VERSION 5.8 ;
BUSBITCHARS "[]" ;
DIVIDERCHAR "/" ;
UNITS
    DATABASE MICRONS 2000 ;
END UNITS

VIA uart_rx_via1_2_8960_1800_2_8_1040_1040
  VIARULE Via1_GEN_HH ;
  CUTSIZE 0.26 0.26 ;
  LAYERS Metal1 Via1 Metal2 ;
  CUTSPACING 0.26 0.26 ;
  ENCLOSURE 0.06 0.06 0.01 0.06 ;
  ROWCOL 2 8 ;
END uart_rx_via1_2_8960_1800_2_8_1040_1040

VIA uart_rx_via2_3_8960_1800_2_8_1040_1040
  VIARULE Via2_GEN_HH ;
  CUTSIZE 0.26 0.26 ;
  LAYERS Metal2 Via2 Metal3 ;
  CUTSPACING 0.26 0.26 ;
  ENCLOSURE 0.01 0.06 0.06 0.01 ;
  ROWCOL 2 8 ;
END uart_rx_via2_3_8960_1800_2_8_1040_1040

VIA uart_rx_via3_4_8960_1800_2_8_1040_1040
  VIARULE Via3_GEN_HH ;
  CUTSIZE 0.26 0.26 ;
  LAYERS Metal3 Via3 Metal4 ;
  CUTSPACING 0.26 0.26 ;
  ENCLOSURE 0.06 0.01 0.29 0.06 ;
  ROWCOL 2 8 ;
END uart_rx_via3_4_8960_1800_2_8_1040_1040

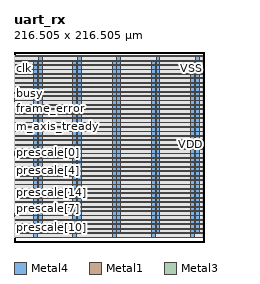
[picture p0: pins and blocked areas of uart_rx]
MACRO uart_rx
  FOREIGN uart_rx 0 0 ;
  CLASS BLOCK ;
  SIZE 216.505 BY 216.505 ;
  PIN VDD
    USE POWER ;
    DIRECTION INOUT ;
    PORT
      LAYER Metal4 ;
        RECT  206.64 9.63 211.12 212.13 ;
        RECT  161.84 9.63 166.32 212.13 ;
        RECT  117.04 9.63 121.52 212.13 ;
        RECT  72.24 9.63 76.72 212.13 ;
        RECT  27.44 9.63 31.92 212.13 ;
      LAYER Metal1 ;
        RECT  2.24 211.23 214.48 212.13 ;
        RECT  2.24 201.15 214.48 202.05 ;
        RECT  2.24 191.07 214.48 191.97 ;
        RECT  2.24 180.99 214.48 181.89 ;
        RECT  2.24 170.91 214.48 171.81 ;
        RECT  2.24 160.83 214.48 161.73 ;
        RECT  2.24 150.75 214.48 151.65 ;
        RECT  2.24 140.67 214.48 141.57 ;
        RECT  2.24 130.59 214.48 131.49 ;
        RECT  2.24 120.51 214.48 121.41 ;
        RECT  2.24 110.43 214.48 111.33 ;
        RECT  2.24 100.35 214.48 101.25 ;
        RECT  2.24 90.27 214.48 91.17 ;
        RECT  2.24 80.19 214.48 81.09 ;
        RECT  2.24 70.11 214.48 71.01 ;
        RECT  2.24 60.03 214.48 60.93 ;
        RECT  2.24 49.95 214.48 50.85 ;
        RECT  2.24 39.87 214.48 40.77 ;
        RECT  2.24 29.79 214.48 30.69 ;
        RECT  2.24 19.71 214.48 20.61 ;
        RECT  2.24 9.63 214.48 10.53 ;
      VIA 208.88 211.68 uart_rx_via3_4_8960_1800_2_8_1040_1040 ;
      VIA 208.88 211.68 uart_rx_via2_3_8960_1800_2_8_1040_1040 ;
      VIA 208.88 211.68 uart_rx_via1_2_8960_1800_2_8_1040_1040 ;
      VIA 208.88 201.6 uart_rx_via3_4_8960_1800_2_8_1040_1040 ;
      VIA 208.88 201.6 uart_rx_via2_3_8960_1800_2_8_1040_1040 ;
      VIA 208.88 201.6 uart_rx_via1_2_8960_1800_2_8_1040_1040 ;
      VIA 208.88 191.52 uart_rx_via3_4_8960_1800_2_8_1040_1040 ;
      VIA 208.88 191.52 uart_rx_via2_3_8960_1800_2_8_1040_1040 ;
      VIA 208.88 191.52 uart_rx_via1_2_8960_1800_2_8_1040_1040 ;
      VIA 208.88 181.44 uart_rx_via3_4_8960_1800_2_8_1040_1040 ;
      VIA 208.88 181.44 uart_rx_via2_3_8960_1800_2_8_1040_1040 ;
      VIA 208.88 181.44 uart_rx_via1_2_8960_1800_2_8_1040_1040 ;
      VIA 208.88 171.36 uart_rx_via3_4_8960_1800_2_8_1040_1040 ;
      VIA 208.88 171.36 uart_rx_via2_3_8960_1800_2_8_1040_1040 ;
      VIA 208.88 171.36 uart_rx_via1_2_8960_1800_2_8_1040_1040 ;
      VIA 208.88 161.28 uart_rx_via3_4_8960_1800_2_8_1040_1040 ;
      VIA 208.88 161.28 uart_rx_via2_3_8960_1800_2_8_1040_1040 ;
      VIA 208.88 161.28 uart_rx_via1_2_8960_1800_2_8_1040_1040 ;
      VIA 208.88 151.2 uart_rx_via3_4_8960_1800_2_8_1040_1040 ;
      VIA 208.88 151.2 uart_rx_via2_3_8960_1800_2_8_1040_1040 ;
      VIA 208.88 151.2 uart_rx_via1_2_8960_1800_2_8_1040_1040 ;
      VIA 208.88 141.12 uart_rx_via3_4_8960_1800_2_8_1040_1040 ;
      VIA 208.88 141.12 uart_rx_via2_3_8960_1800_2_8_1040_1040 ;
      VIA 208.88 141.12 uart_rx_via1_2_8960_1800_2_8_1040_1040 ;
      VIA 208.88 131.04 uart_rx_via3_4_8960_1800_2_8_1040_1040 ;
      VIA 208.88 131.04 uart_rx_via2_3_8960_1800_2_8_1040_1040 ;
      VIA 208.88 131.04 uart_rx_via1_2_8960_1800_2_8_1040_1040 ;
      VIA 208.88 120.96 uart_rx_via3_4_8960_1800_2_8_1040_1040 ;
      VIA 208.88 120.96 uart_rx_via2_3_8960_1800_2_8_1040_1040 ;
      VIA 208.88 120.96 uart_rx_via1_2_8960_1800_2_8_1040_1040 ;
      VIA 208.88 110.88 uart_rx_via3_4_8960_1800_2_8_1040_1040 ;
      VIA 208.88 110.88 uart_rx_via2_3_8960_1800_2_8_1040_1040 ;
      VIA 208.88 110.88 uart_rx_via1_2_8960_1800_2_8_1040_1040 ;
      VIA 208.88 100.8 uart_rx_via3_4_8960_1800_2_8_1040_1040 ;
      VIA 208.88 100.8 uart_rx_via2_3_8960_1800_2_8_1040_1040 ;
      VIA 208.88 100.8 uart_rx_via1_2_8960_1800_2_8_1040_1040 ;
      VIA 208.88 90.72 uart_rx_via3_4_8960_1800_2_8_1040_1040 ;
      VIA 208.88 90.72 uart_rx_via2_3_8960_1800_2_8_1040_1040 ;
      VIA 208.88 90.72 uart_rx_via1_2_8960_1800_2_8_1040_1040 ;
      VIA 208.88 80.64 uart_rx_via3_4_8960_1800_2_8_1040_1040 ;
      VIA 208.88 80.64 uart_rx_via2_3_8960_1800_2_8_1040_1040 ;
      VIA 208.88 80.64 uart_rx_via1_2_8960_1800_2_8_1040_1040 ;
      VIA 208.88 70.56 uart_rx_via3_4_8960_1800_2_8_1040_1040 ;
      VIA 208.88 70.56 uart_rx_via2_3_8960_1800_2_8_1040_1040 ;
      VIA 208.88 70.56 uart_rx_via1_2_8960_1800_2_8_1040_1040 ;
      VIA 208.88 60.48 uart_rx_via3_4_8960_1800_2_8_1040_1040 ;
      VIA 208.88 60.48 uart_rx_via2_3_8960_1800_2_8_1040_1040 ;
      VIA 208.88 60.48 uart_rx_via1_2_8960_1800_2_8_1040_1040 ;
      VIA 208.88 50.4 uart_rx_via3_4_8960_1800_2_8_1040_1040 ;
      VIA 208.88 50.4 uart_rx_via2_3_8960_1800_2_8_1040_1040 ;
      VIA 208.88 50.4 uart_rx_via1_2_8960_1800_2_8_1040_1040 ;
      VIA 208.88 40.32 uart_rx_via3_4_8960_1800_2_8_1040_1040 ;
      VIA 208.88 40.32 uart_rx_via2_3_8960_1800_2_8_1040_1040 ;
      VIA 208.88 40.32 uart_rx_via1_2_8960_1800_2_8_1040_1040 ;
      VIA 208.88 30.24 uart_rx_via3_4_8960_1800_2_8_1040_1040 ;
      VIA 208.88 30.24 uart_rx_via2_3_8960_1800_2_8_1040_1040 ;
      VIA 208.88 30.24 uart_rx_via1_2_8960_1800_2_8_1040_1040 ;
      VIA 208.88 20.16 uart_rx_via3_4_8960_1800_2_8_1040_1040 ;
      VIA 208.88 20.16 uart_rx_via2_3_8960_1800_2_8_1040_1040 ;
      VIA 208.88 20.16 uart_rx_via1_2_8960_1800_2_8_1040_1040 ;
      VIA 208.88 10.08 uart_rx_via3_4_8960_1800_2_8_1040_1040 ;
      VIA 208.88 10.08 uart_rx_via2_3_8960_1800_2_8_1040_1040 ;
      VIA 208.88 10.08 uart_rx_via1_2_8960_1800_2_8_1040_1040 ;
      VIA 164.08 211.68 uart_rx_via3_4_8960_1800_2_8_1040_1040 ;
      VIA 164.08 211.68 uart_rx_via2_3_8960_1800_2_8_1040_1040 ;
      VIA 164.08 211.68 uart_rx_via1_2_8960_1800_2_8_1040_1040 ;
      VIA 164.08 201.6 uart_rx_via3_4_8960_1800_2_8_1040_1040 ;
      VIA 164.08 201.6 uart_rx_via2_3_8960_1800_2_8_1040_1040 ;
      VIA 164.08 201.6 uart_rx_via1_2_8960_1800_2_8_1040_1040 ;
      VIA 164.08 191.52 uart_rx_via3_4_8960_1800_2_8_1040_1040 ;
      VIA 164.08 191.52 uart_rx_via2_3_8960_1800_2_8_1040_1040 ;
      VIA 164.08 191.52 uart_rx_via1_2_8960_1800_2_8_1040_1040 ;
      VIA 164.08 181.44 uart_rx_via3_4_8960_1800_2_8_1040_1040 ;
      VIA 164.08 181.44 uart_rx_via2_3_8960_1800_2_8_1040_1040 ;
      VIA 164.08 181.44 uart_rx_via1_2_8960_1800_2_8_1040_1040 ;
      VIA 164.08 171.36 uart_rx_via3_4_8960_1800_2_8_1040_1040 ;
      VIA 164.08 171.36 uart_rx_via2_3_8960_1800_2_8_1040_1040 ;
      VIA 164.08 171.36 uart_rx_via1_2_8960_1800_2_8_1040_1040 ;
      VIA 164.08 161.28 uart_rx_via3_4_8960_1800_2_8_1040_1040 ;
      VIA 164.08 161.28 uart_rx_via2_3_8960_1800_2_8_1040_1040 ;
      VIA 164.08 161.28 uart_rx_via1_2_8960_1800_2_8_1040_1040 ;
      VIA 164.08 151.2 uart_rx_via3_4_8960_1800_2_8_1040_1040 ;
      VIA 164.08 151.2 uart_rx_via2_3_8960_1800_2_8_1040_1040 ;
      VIA 164.08 151.2 uart_rx_via1_2_8960_1800_2_8_1040_1040 ;
      VIA 164.08 141.12 uart_rx_via3_4_8960_1800_2_8_1040_1040 ;
      VIA 164.08 141.12 uart_rx_via2_3_8960_1800_2_8_1040_1040 ;
      VIA 164.08 141.12 uart_rx_via1_2_8960_1800_2_8_1040_1040 ;
      VIA 164.08 131.04 uart_rx_via3_4_8960_1800_2_8_1040_1040 ;
      VIA 164.08 131.04 uart_rx_via2_3_8960_1800_2_8_1040_1040 ;
      VIA 164.08 131.04 uart_rx_via1_2_8960_1800_2_8_1040_1040 ;
      VIA 164.08 120.96 uart_rx_via3_4_8960_1800_2_8_1040_1040 ;
      VIA 164.08 120.96 uart_rx_via2_3_8960_1800_2_8_1040_1040 ;
      VIA 164.08 120.96 uart_rx_via1_2_8960_1800_2_8_1040_1040 ;
      VIA 164.08 110.88 uart_rx_via3_4_8960_1800_2_8_1040_1040 ;
      VIA 164.08 110.88 uart_rx_via2_3_8960_1800_2_8_1040_1040 ;
      VIA 164.08 110.88 uart_rx_via1_2_8960_1800_2_8_1040_1040 ;
      VIA 164.08 100.8 uart_rx_via3_4_8960_1800_2_8_1040_1040 ;
      VIA 164.08 100.8 uart_rx_via2_3_8960_1800_2_8_1040_1040 ;
      VIA 164.08 100.8 uart_rx_via1_2_8960_1800_2_8_1040_1040 ;
      VIA 164.08 90.72 uart_rx_via3_4_8960_1800_2_8_1040_1040 ;
      VIA 164.08 90.72 uart_rx_via2_3_8960_1800_2_8_1040_1040 ;
      VIA 164.08 90.72 uart_rx_via1_2_8960_1800_2_8_1040_1040 ;
      VIA 164.08 80.64 uart_rx_via3_4_8960_1800_2_8_1040_1040 ;
      VIA 164.08 80.64 uart_rx_via2_3_8960_1800_2_8_1040_1040 ;
      VIA 164.08 80.64 uart_rx_via1_2_8960_1800_2_8_1040_1040 ;
      VIA 164.08 70.56 uart_rx_via3_4_8960_1800_2_8_1040_1040 ;
      VIA 164.08 70.56 uart_rx_via2_3_8960_1800_2_8_1040_1040 ;
      VIA 164.08 70.56 uart_rx_via1_2_8960_1800_2_8_1040_1040 ;
      VIA 164.08 60.48 uart_rx_via3_4_8960_1800_2_8_1040_1040 ;
      VIA 164.08 60.48 uart_rx_via2_3_8960_1800_2_8_1040_1040 ;
      VIA 164.08 60.48 uart_rx_via1_2_8960_1800_2_8_1040_1040 ;
      VIA 164.08 50.4 uart_rx_via3_4_8960_1800_2_8_1040_1040 ;
      VIA 164.08 50.4 uart_rx_via2_3_8960_1800_2_8_1040_1040 ;
      VIA 164.08 50.4 uart_rx_via1_2_8960_1800_2_8_1040_1040 ;
      VIA 164.08 40.32 uart_rx_via3_4_8960_1800_2_8_1040_1040 ;
      VIA 164.08 40.32 uart_rx_via2_3_8960_1800_2_8_1040_1040 ;
      VIA 164.08 40.32 uart_rx_via1_2_8960_1800_2_8_1040_1040 ;
      VIA 164.08 30.24 uart_rx_via3_4_8960_1800_2_8_1040_1040 ;
      VIA 164.08 30.24 uart_rx_via2_3_8960_1800_2_8_1040_1040 ;
      VIA 164.08 30.24 uart_rx_via1_2_8960_1800_2_8_1040_1040 ;
      VIA 164.08 20.16 uart_rx_via3_4_8960_1800_2_8_1040_1040 ;
      VIA 164.08 20.16 uart_rx_via2_3_8960_1800_2_8_1040_1040 ;
      VIA 164.08 20.16 uart_rx_via1_2_8960_1800_2_8_1040_1040 ;
      VIA 164.08 10.08 uart_rx_via3_4_8960_1800_2_8_1040_1040 ;
      VIA 164.08 10.08 uart_rx_via2_3_8960_1800_2_8_1040_1040 ;
      VIA 164.08 10.08 uart_rx_via1_2_8960_1800_2_8_1040_1040 ;
      VIA 119.28 211.68 uart_rx_via3_4_8960_1800_2_8_1040_1040 ;
      VIA 119.28 211.68 uart_rx_via2_3_8960_1800_2_8_1040_1040 ;
      VIA 119.28 211.68 uart_rx_via1_2_8960_1800_2_8_1040_1040 ;
      VIA 119.28 201.6 uart_rx_via3_4_8960_1800_2_8_1040_1040 ;
      VIA 119.28 201.6 uart_rx_via2_3_8960_1800_2_8_1040_1040 ;
      VIA 119.28 201.6 uart_rx_via1_2_8960_1800_2_8_1040_1040 ;
      VIA 119.28 191.52 uart_rx_via3_4_8960_1800_2_8_1040_1040 ;
      VIA 119.28 191.52 uart_rx_via2_3_8960_1800_2_8_1040_1040 ;
      VIA 119.28 191.52 uart_rx_via1_2_8960_1800_2_8_1040_1040 ;
      VIA 119.28 181.44 uart_rx_via3_4_8960_1800_2_8_1040_1040 ;
      VIA 119.28 181.44 uart_rx_via2_3_8960_1800_2_8_1040_1040 ;
      VIA 119.28 181.44 uart_rx_via1_2_8960_1800_2_8_1040_1040 ;
      VIA 119.28 171.36 uart_rx_via3_4_8960_1800_2_8_1040_1040 ;
      VIA 119.28 171.36 uart_rx_via2_3_8960_1800_2_8_1040_1040 ;
      VIA 119.28 171.36 uart_rx_via1_2_8960_1800_2_8_1040_1040 ;
      VIA 119.28 161.28 uart_rx_via3_4_8960_1800_2_8_1040_1040 ;
      VIA 119.28 161.28 uart_rx_via2_3_8960_1800_2_8_1040_1040 ;
      VIA 119.28 161.28 uart_rx_via1_2_8960_1800_2_8_1040_1040 ;
      VIA 119.28 151.2 uart_rx_via3_4_8960_1800_2_8_1040_1040 ;
      VIA 119.28 151.2 uart_rx_via2_3_8960_1800_2_8_1040_1040 ;
      VIA 119.28 151.2 uart_rx_via1_2_8960_1800_2_8_1040_1040 ;
      VIA 119.28 141.12 uart_rx_via3_4_8960_1800_2_8_1040_1040 ;
      VIA 119.28 141.12 uart_rx_via2_3_8960_1800_2_8_1040_1040 ;
      VIA 119.28 141.12 uart_rx_via1_2_8960_1800_2_8_1040_1040 ;
      VIA 119.28 131.04 uart_rx_via3_4_8960_1800_2_8_1040_1040 ;
      VIA 119.28 131.04 uart_rx_via2_3_8960_1800_2_8_1040_1040 ;
      VIA 119.28 131.04 uart_rx_via1_2_8960_1800_2_8_1040_1040 ;
      VIA 119.28 120.96 uart_rx_via3_4_8960_1800_2_8_1040_1040 ;
      VIA 119.28 120.96 uart_rx_via2_3_8960_1800_2_8_1040_1040 ;
      VIA 119.28 120.96 uart_rx_via1_2_8960_1800_2_8_1040_1040 ;
      VIA 119.28 110.88 uart_rx_via3_4_8960_1800_2_8_1040_1040 ;
      VIA 119.28 110.88 uart_rx_via2_3_8960_1800_2_8_1040_1040 ;
      VIA 119.28 110.88 uart_rx_via1_2_8960_1800_2_8_1040_1040 ;
      VIA 119.28 100.8 uart_rx_via3_4_8960_1800_2_8_1040_1040 ;
      VIA 119.28 100.8 uart_rx_via2_3_8960_1800_2_8_1040_1040 ;
      VIA 119.28 100.8 uart_rx_via1_2_8960_1800_2_8_1040_1040 ;
      VIA 119.28 90.72 uart_rx_via3_4_8960_1800_2_8_1040_1040 ;
      VIA 119.28 90.72 uart_rx_via2_3_8960_1800_2_8_1040_1040 ;
      VIA 119.28 90.72 uart_rx_via1_2_8960_1800_2_8_1040_1040 ;
      VIA 119.28 80.64 uart_rx_via3_4_8960_1800_2_8_1040_1040 ;
      VIA 119.28 80.64 uart_rx_via2_3_8960_1800_2_8_1040_1040 ;
      VIA 119.28 80.64 uart_rx_via1_2_8960_1800_2_8_1040_1040 ;
      VIA 119.28 70.56 uart_rx_via3_4_8960_1800_2_8_1040_1040 ;
      VIA 119.28 70.56 uart_rx_via2_3_8960_1800_2_8_1040_1040 ;
      VIA 119.28 70.56 uart_rx_via1_2_8960_1800_2_8_1040_1040 ;
      VIA 119.28 60.48 uart_rx_via3_4_8960_1800_2_8_1040_1040 ;
      VIA 119.28 60.48 uart_rx_via2_3_8960_1800_2_8_1040_1040 ;
      VIA 119.28 60.48 uart_rx_via1_2_8960_1800_2_8_1040_1040 ;
      VIA 119.28 50.4 uart_rx_via3_4_8960_1800_2_8_1040_1040 ;
      VIA 119.28 50.4 uart_rx_via2_3_8960_1800_2_8_1040_1040 ;
      VIA 119.28 50.4 uart_rx_via1_2_8960_1800_2_8_1040_1040 ;
      VIA 119.28 40.32 uart_rx_via3_4_8960_1800_2_8_1040_1040 ;
      VIA 119.28 40.32 uart_rx_via2_3_8960_1800_2_8_1040_1040 ;
      VIA 119.28 40.32 uart_rx_via1_2_8960_1800_2_8_1040_1040 ;
      VIA 119.28 30.24 uart_rx_via3_4_8960_1800_2_8_1040_1040 ;
      VIA 119.28 30.24 uart_rx_via2_3_8960_1800_2_8_1040_1040 ;
      VIA 119.28 30.24 uart_rx_via1_2_8960_1800_2_8_1040_1040 ;
      VIA 119.28 20.16 uart_rx_via3_4_8960_1800_2_8_1040_1040 ;
      VIA 119.28 20.16 uart_rx_via2_3_8960_1800_2_8_1040_1040 ;
      VIA 119.28 20.16 uart_rx_via1_2_8960_1800_2_8_1040_1040 ;
      VIA 119.28 10.08 uart_rx_via3_4_8960_1800_2_8_1040_1040 ;
      VIA 119.28 10.08 uart_rx_via2_3_8960_1800_2_8_1040_1040 ;
      VIA 119.28 10.08 uart_rx_via1_2_8960_1800_2_8_1040_1040 ;
      VIA 74.48 211.68 uart_rx_via3_4_8960_1800_2_8_1040_1040 ;
      VIA 74.48 211.68 uart_rx_via2_3_8960_1800_2_8_1040_1040 ;
      VIA 74.48 211.68 uart_rx_via1_2_8960_1800_2_8_1040_1040 ;
      VIA 74.48 201.6 uart_rx_via3_4_8960_1800_2_8_1040_1040 ;
      VIA 74.48 201.6 uart_rx_via2_3_8960_1800_2_8_1040_1040 ;
      VIA 74.48 201.6 uart_rx_via1_2_8960_1800_2_8_1040_1040 ;
      VIA 74.48 191.52 uart_rx_via3_4_8960_1800_2_8_1040_1040 ;
      VIA 74.48 191.52 uart_rx_via2_3_8960_1800_2_8_1040_1040 ;
      VIA 74.48 191.52 uart_rx_via1_2_8960_1800_2_8_1040_1040 ;
      VIA 74.48 181.44 uart_rx_via3_4_8960_1800_2_8_1040_1040 ;
      VIA 74.48 181.44 uart_rx_via2_3_8960_1800_2_8_1040_1040 ;
      VIA 74.48 181.44 uart_rx_via1_2_8960_1800_2_8_1040_1040 ;
      VIA 74.48 171.36 uart_rx_via3_4_8960_1800_2_8_1040_1040 ;
      VIA 74.48 171.36 uart_rx_via2_3_8960_1800_2_8_1040_1040 ;
      VIA 74.48 171.36 uart_rx_via1_2_8960_1800_2_8_1040_1040 ;
      VIA 74.48 161.28 uart_rx_via3_4_8960_1800_2_8_1040_1040 ;
      VIA 74.48 161.28 uart_rx_via2_3_8960_1800_2_8_1040_1040 ;
      VIA 74.48 161.28 uart_rx_via1_2_8960_1800_2_8_1040_1040 ;
      VIA 74.48 151.2 uart_rx_via3_4_8960_1800_2_8_1040_1040 ;
      VIA 74.48 151.2 uart_rx_via2_3_8960_1800_2_8_1040_1040 ;
      VIA 74.48 151.2 uart_rx_via1_2_8960_1800_2_8_1040_1040 ;
      VIA 74.48 141.12 uart_rx_via3_4_8960_1800_2_8_1040_1040 ;
      VIA 74.48 141.12 uart_rx_via2_3_8960_1800_2_8_1040_1040 ;
      VIA 74.48 141.12 uart_rx_via1_2_8960_1800_2_8_1040_1040 ;
      VIA 74.48 131.04 uart_rx_via3_4_8960_1800_2_8_1040_1040 ;
      VIA 74.48 131.04 uart_rx_via2_3_8960_1800_2_8_1040_1040 ;
      VIA 74.48 131.04 uart_rx_via1_2_8960_1800_2_8_1040_1040 ;
      VIA 74.48 120.96 uart_rx_via3_4_8960_1800_2_8_1040_1040 ;
      VIA 74.48 120.96 uart_rx_via2_3_8960_1800_2_8_1040_1040 ;
      VIA 74.48 120.96 uart_rx_via1_2_8960_1800_2_8_1040_1040 ;
      VIA 74.48 110.88 uart_rx_via3_4_8960_1800_2_8_1040_1040 ;
      VIA 74.48 110.88 uart_rx_via2_3_8960_1800_2_8_1040_1040 ;
      VIA 74.48 110.88 uart_rx_via1_2_8960_1800_2_8_1040_1040 ;
      VIA 74.48 100.8 uart_rx_via3_4_8960_1800_2_8_1040_1040 ;
      VIA 74.48 100.8 uart_rx_via2_3_8960_1800_2_8_1040_1040 ;
      VIA 74.48 100.8 uart_rx_via1_2_8960_1800_2_8_1040_1040 ;
      VIA 74.48 90.72 uart_rx_via3_4_8960_1800_2_8_1040_1040 ;
      VIA 74.48 90.72 uart_rx_via2_3_8960_1800_2_8_1040_1040 ;
      VIA 74.48 90.72 uart_rx_via1_2_8960_1800_2_8_1040_1040 ;
      VIA 74.48 80.64 uart_rx_via3_4_8960_1800_2_8_1040_1040 ;
      VIA 74.48 80.64 uart_rx_via2_3_8960_1800_2_8_1040_1040 ;
      VIA 74.48 80.64 uart_rx_via1_2_8960_1800_2_8_1040_1040 ;
      VIA 74.48 70.56 uart_rx_via3_4_8960_1800_2_8_1040_1040 ;
      VIA 74.48 70.56 uart_rx_via2_3_8960_1800_2_8_1040_1040 ;
      VIA 74.48 70.56 uart_rx_via1_2_8960_1800_2_8_1040_1040 ;
      VIA 74.48 60.48 uart_rx_via3_4_8960_1800_2_8_1040_1040 ;
      VIA 74.48 60.48 uart_rx_via2_3_8960_1800_2_8_1040_1040 ;
      VIA 74.48 60.48 uart_rx_via1_2_8960_1800_2_8_1040_1040 ;
      VIA 74.48 50.4 uart_rx_via3_4_8960_1800_2_8_1040_1040 ;
      VIA 74.48 50.4 uart_rx_via2_3_8960_1800_2_8_1040_1040 ;
      VIA 74.48 50.4 uart_rx_via1_2_8960_1800_2_8_1040_1040 ;
      VIA 74.48 40.32 uart_rx_via3_4_8960_1800_2_8_1040_1040 ;
      VIA 74.48 40.32 uart_rx_via2_3_8960_1800_2_8_1040_1040 ;
      VIA 74.48 40.32 uart_rx_via1_2_8960_1800_2_8_1040_1040 ;
      VIA 74.48 30.24 uart_rx_via3_4_8960_1800_2_8_1040_1040 ;
      VIA 74.48 30.24 uart_rx_via2_3_8960_1800_2_8_1040_1040 ;
      VIA 74.48 30.24 uart_rx_via1_2_8960_1800_2_8_1040_1040 ;
      VIA 74.48 20.16 uart_rx_via3_4_8960_1800_2_8_1040_1040 ;
      VIA 74.48 20.16 uart_rx_via2_3_8960_1800_2_8_1040_1040 ;
      VIA 74.48 20.16 uart_rx_via1_2_8960_1800_2_8_1040_1040 ;
      VIA 74.48 10.08 uart_rx_via3_4_8960_1800_2_8_1040_1040 ;
      VIA 74.48 10.08 uart_rx_via2_3_8960_1800_2_8_1040_1040 ;
      VIA 74.48 10.08 uart_rx_via1_2_8960_1800_2_8_1040_1040 ;
      VIA 29.68 211.68 uart_rx_via3_4_8960_1800_2_8_1040_1040 ;
      VIA 29.68 211.68 uart_rx_via2_3_8960_1800_2_8_1040_1040 ;
      VIA 29.68 211.68 uart_rx_via1_2_8960_1800_2_8_1040_1040 ;
      VIA 29.68 201.6 uart_rx_via3_4_8960_1800_2_8_1040_1040 ;
      VIA 29.68 201.6 uart_rx_via2_3_8960_1800_2_8_1040_1040 ;
      VIA 29.68 201.6 uart_rx_via1_2_8960_1800_2_8_1040_1040 ;
      VIA 29.68 191.52 uart_rx_via3_4_8960_1800_2_8_1040_1040 ;
      VIA 29.68 191.52 uart_rx_via2_3_8960_1800_2_8_1040_1040 ;
      VIA 29.68 191.52 uart_rx_via1_2_8960_1800_2_8_1040_1040 ;
      VIA 29.68 181.44 uart_rx_via3_4_8960_1800_2_8_1040_1040 ;
      VIA 29.68 181.44 uart_rx_via2_3_8960_1800_2_8_1040_1040 ;
      VIA 29.68 181.44 uart_rx_via1_2_8960_1800_2_8_1040_1040 ;
      VIA 29.68 171.36 uart_rx_via3_4_8960_1800_2_8_1040_1040 ;
      VIA 29.68 171.36 uart_rx_via2_3_8960_1800_2_8_1040_1040 ;
      VIA 29.68 171.36 uart_rx_via1_2_8960_1800_2_8_1040_1040 ;
      VIA 29.68 161.28 uart_rx_via3_4_8960_1800_2_8_1040_1040 ;
      VIA 29.68 161.28 uart_rx_via2_3_8960_1800_2_8_1040_1040 ;
      VIA 29.68 161.28 uart_rx_via1_2_8960_1800_2_8_1040_1040 ;
      VIA 29.68 151.2 uart_rx_via3_4_8960_1800_2_8_1040_1040 ;
      VIA 29.68 151.2 uart_rx_via2_3_8960_1800_2_8_1040_1040 ;
      VIA 29.68 151.2 uart_rx_via1_2_8960_1800_2_8_1040_1040 ;
      VIA 29.68 141.12 uart_rx_via3_4_8960_1800_2_8_1040_1040 ;
      VIA 29.68 141.12 uart_rx_via2_3_8960_1800_2_8_1040_1040 ;
      VIA 29.68 141.12 uart_rx_via1_2_8960_1800_2_8_1040_1040 ;
      VIA 29.68 131.04 uart_rx_via3_4_8960_1800_2_8_1040_1040 ;
      VIA 29.68 131.04 uart_rx_via2_3_8960_1800_2_8_1040_1040 ;
      VIA 29.68 131.04 uart_rx_via1_2_8960_1800_2_8_1040_1040 ;
      VIA 29.68 120.96 uart_rx_via3_4_8960_1800_2_8_1040_1040 ;
      VIA 29.68 120.96 uart_rx_via2_3_8960_1800_2_8_1040_1040 ;
      VIA 29.68 120.96 uart_rx_via1_2_8960_1800_2_8_1040_1040 ;
      VIA 29.68 110.88 uart_rx_via3_4_8960_1800_2_8_1040_1040 ;
      VIA 29.68 110.88 uart_rx_via2_3_8960_1800_2_8_1040_1040 ;
      VIA 29.68 110.88 uart_rx_via1_2_8960_1800_2_8_1040_1040 ;
      VIA 29.68 100.8 uart_rx_via3_4_8960_1800_2_8_1040_1040 ;
      VIA 29.68 100.8 uart_rx_via2_3_8960_1800_2_8_1040_1040 ;
      VIA 29.68 100.8 uart_rx_via1_2_8960_1800_2_8_1040_1040 ;
      VIA 29.68 90.72 uart_rx_via3_4_8960_1800_2_8_1040_1040 ;
      VIA 29.68 90.72 uart_rx_via2_3_8960_1800_2_8_1040_1040 ;
      VIA 29.68 90.72 uart_rx_via1_2_8960_1800_2_8_1040_1040 ;
      VIA 29.68 80.64 uart_rx_via3_4_8960_1800_2_8_1040_1040 ;
      VIA 29.68 80.64 uart_rx_via2_3_8960_1800_2_8_1040_1040 ;
      VIA 29.68 80.64 uart_rx_via1_2_8960_1800_2_8_1040_1040 ;
      VIA 29.68 70.56 uart_rx_via3_4_8960_1800_2_8_1040_1040 ;
      VIA 29.68 70.56 uart_rx_via2_3_8960_1800_2_8_1040_1040 ;
      VIA 29.68 70.56 uart_rx_via1_2_8960_1800_2_8_1040_1040 ;
      VIA 29.68 60.48 uart_rx_via3_4_8960_1800_2_8_1040_1040 ;
      VIA 29.68 60.48 uart_rx_via2_3_8960_1800_2_8_1040_1040 ;
      VIA 29.68 60.48 uart_rx_via1_2_8960_1800_2_8_1040_1040 ;
      VIA 29.68 50.4 uart_rx_via3_4_8960_1800_2_8_1040_1040 ;
      VIA 29.68 50.4 uart_rx_via2_3_8960_1800_2_8_1040_1040 ;
      VIA 29.68 50.4 uart_rx_via1_2_8960_1800_2_8_1040_1040 ;
      VIA 29.68 40.32 uart_rx_via3_4_8960_1800_2_8_1040_1040 ;
      VIA 29.68 40.32 uart_rx_via2_3_8960_1800_2_8_1040_1040 ;
      VIA 29.68 40.32 uart_rx_via1_2_8960_1800_2_8_1040_1040 ;
      VIA 29.68 30.24 uart_rx_via3_4_8960_1800_2_8_1040_1040 ;
      VIA 29.68 30.24 uart_rx_via2_3_8960_1800_2_8_1040_1040 ;
      VIA 29.68 30.24 uart_rx_via1_2_8960_1800_2_8_1040_1040 ;
      VIA 29.68 20.16 uart_rx_via3_4_8960_1800_2_8_1040_1040 ;
      VIA 29.68 20.16 uart_rx_via2_3_8960_1800_2_8_1040_1040 ;
      VIA 29.68 20.16 uart_rx_via1_2_8960_1800_2_8_1040_1040 ;
      VIA 29.68 10.08 uart_rx_via3_4_8960_1800_2_8_1040_1040 ;
      VIA 29.68 10.08 uart_rx_via2_3_8960_1800_2_8_1040_1040 ;
      VIA 29.68 10.08 uart_rx_via1_2_8960_1800_2_8_1040_1040 ;
    END
  END VDD
  PIN VSS
    USE GROUND ;
    DIRECTION INOUT ;
    PORT
      LAYER Metal4 ;
        RECT  201.6 4.59 206.08 207.09 ;
        RECT  156.8 4.59 161.28 207.09 ;
        RECT  112 4.59 116.48 207.09 ;
        RECT  67.2 4.59 71.68 207.09 ;
        RECT  22.4 4.59 26.88 207.09 ;
      LAYER Metal1 ;
        RECT  2.24 206.19 214.48 207.09 ;
        RECT  2.24 196.11 214.48 197.01 ;
        RECT  2.24 186.03 214.48 186.93 ;
        RECT  2.24 175.95 214.48 176.85 ;
        RECT  2.24 165.87 214.48 166.77 ;
        RECT  2.24 155.79 214.48 156.69 ;
        RECT  2.24 145.71 214.48 146.61 ;
        RECT  2.24 135.63 214.48 136.53 ;
        RECT  2.24 125.55 214.48 126.45 ;
        RECT  2.24 115.47 214.48 116.37 ;
        RECT  2.24 105.39 214.48 106.29 ;
        RECT  2.24 95.31 214.48 96.21 ;
        RECT  2.24 85.23 214.48 86.13 ;
        RECT  2.24 75.15 214.48 76.05 ;
        RECT  2.24 65.07 214.48 65.97 ;
        RECT  2.24 54.99 214.48 55.89 ;
        RECT  2.24 44.91 214.48 45.81 ;
        RECT  2.24 34.83 214.48 35.73 ;
        RECT  2.24 24.75 214.48 25.65 ;
        RECT  2.24 14.67 214.48 15.57 ;
        RECT  2.24 4.59 214.48 5.49 ;
      VIA 203.84 206.64 uart_rx_via3_4_8960_1800_2_8_1040_1040 ;
      VIA 203.84 206.64 uart_rx_via2_3_8960_1800_2_8_1040_1040 ;
      VIA 203.84 206.64 uart_rx_via1_2_8960_1800_2_8_1040_1040 ;
      VIA 203.84 196.56 uart_rx_via3_4_8960_1800_2_8_1040_1040 ;
      VIA 203.84 196.56 uart_rx_via2_3_8960_1800_2_8_1040_1040 ;
      VIA 203.84 196.56 uart_rx_via1_2_8960_1800_2_8_1040_1040 ;
      VIA 203.84 186.48 uart_rx_via3_4_8960_1800_2_8_1040_1040 ;
      VIA 203.84 186.48 uart_rx_via2_3_8960_1800_2_8_1040_1040 ;
      VIA 203.84 186.48 uart_rx_via1_2_8960_1800_2_8_1040_1040 ;
      VIA 203.84 176.4 uart_rx_via3_4_8960_1800_2_8_1040_1040 ;
      VIA 203.84 176.4 uart_rx_via2_3_8960_1800_2_8_1040_1040 ;
      VIA 203.84 176.4 uart_rx_via1_2_8960_1800_2_8_1040_1040 ;
      VIA 203.84 166.32 uart_rx_via3_4_8960_1800_2_8_1040_1040 ;
      VIA 203.84 166.32 uart_rx_via2_3_8960_1800_2_8_1040_1040 ;
      VIA 203.84 166.32 uart_rx_via1_2_8960_1800_2_8_1040_1040 ;
      VIA 203.84 156.24 uart_rx_via3_4_8960_1800_2_8_1040_1040 ;
      VIA 203.84 156.24 uart_rx_via2_3_8960_1800_2_8_1040_1040 ;
      VIA 203.84 156.24 uart_rx_via1_2_8960_1800_2_8_1040_1040 ;
      VIA 203.84 146.16 uart_rx_via3_4_8960_1800_2_8_1040_1040 ;
      VIA 203.84 146.16 uart_rx_via2_3_8960_1800_2_8_1040_1040 ;
      VIA 203.84 146.16 uart_rx_via1_2_8960_1800_2_8_1040_1040 ;
      VIA 203.84 136.08 uart_rx_via3_4_8960_1800_2_8_1040_1040 ;
      VIA 203.84 136.08 uart_rx_via2_3_8960_1800_2_8_1040_1040 ;
      VIA 203.84 136.08 uart_rx_via1_2_8960_1800_2_8_1040_1040 ;
      VIA 203.84 126 uart_rx_via3_4_8960_1800_2_8_1040_1040 ;
      VIA 203.84 126 uart_rx_via2_3_8960_1800_2_8_1040_1040 ;
      VIA 203.84 126 uart_rx_via1_2_8960_1800_2_8_1040_1040 ;
      VIA 203.84 115.92 uart_rx_via3_4_8960_1800_2_8_1040_1040 ;
      VIA 203.84 115.92 uart_rx_via2_3_8960_1800_2_8_1040_1040 ;
      VIA 203.84 115.92 uart_rx_via1_2_8960_1800_2_8_1040_1040 ;
      VIA 203.84 105.84 uart_rx_via3_4_8960_1800_2_8_1040_1040 ;
      VIA 203.84 105.84 uart_rx_via2_3_8960_1800_2_8_1040_1040 ;
      VIA 203.84 105.84 uart_rx_via1_2_8960_1800_2_8_1040_1040 ;
      VIA 203.84 95.76 uart_rx_via3_4_8960_1800_2_8_1040_1040 ;
      VIA 203.84 95.76 uart_rx_via2_3_8960_1800_2_8_1040_1040 ;
      VIA 203.84 95.76 uart_rx_via1_2_8960_1800_2_8_1040_1040 ;
      VIA 203.84 85.68 uart_rx_via3_4_8960_1800_2_8_1040_1040 ;
      VIA 203.84 85.68 uart_rx_via2_3_8960_1800_2_8_1040_1040 ;
      VIA 203.84 85.68 uart_rx_via1_2_8960_1800_2_8_1040_1040 ;
      VIA 203.84 75.6 uart_rx_via3_4_8960_1800_2_8_1040_1040 ;
      VIA 203.84 75.6 uart_rx_via2_3_8960_1800_2_8_1040_1040 ;
      VIA 203.84 75.6 uart_rx_via1_2_8960_1800_2_8_1040_1040 ;
      VIA 203.84 65.52 uart_rx_via3_4_8960_1800_2_8_1040_1040 ;
      VIA 203.84 65.52 uart_rx_via2_3_8960_1800_2_8_1040_1040 ;
      VIA 203.84 65.52 uart_rx_via1_2_8960_1800_2_8_1040_1040 ;
      VIA 203.84 55.44 uart_rx_via3_4_8960_1800_2_8_1040_1040 ;
      VIA 203.84 55.44 uart_rx_via2_3_8960_1800_2_8_1040_1040 ;
      VIA 203.84 55.44 uart_rx_via1_2_8960_1800_2_8_1040_1040 ;
      VIA 203.84 45.36 uart_rx_via3_4_8960_1800_2_8_1040_1040 ;
      VIA 203.84 45.36 uart_rx_via2_3_8960_1800_2_8_1040_1040 ;
      VIA 203.84 45.36 uart_rx_via1_2_8960_1800_2_8_1040_1040 ;
      VIA 203.84 35.28 uart_rx_via3_4_8960_1800_2_8_1040_1040 ;
      VIA 203.84 35.28 uart_rx_via2_3_8960_1800_2_8_1040_1040 ;
      VIA 203.84 35.28 uart_rx_via1_2_8960_1800_2_8_1040_1040 ;
      VIA 203.84 25.2 uart_rx_via3_4_8960_1800_2_8_1040_1040 ;
      VIA 203.84 25.2 uart_rx_via2_3_8960_1800_2_8_1040_1040 ;
      VIA 203.84 25.2 uart_rx_via1_2_8960_1800_2_8_1040_1040 ;
      VIA 203.84 15.12 uart_rx_via3_4_8960_1800_2_8_1040_1040 ;
      VIA 203.84 15.12 uart_rx_via2_3_8960_1800_2_8_1040_1040 ;
      VIA 203.84 15.12 uart_rx_via1_2_8960_1800_2_8_1040_1040 ;
      VIA 203.84 5.04 uart_rx_via3_4_8960_1800_2_8_1040_1040 ;
      VIA 203.84 5.04 uart_rx_via2_3_8960_1800_2_8_1040_1040 ;
      VIA 203.84 5.04 uart_rx_via1_2_8960_1800_2_8_1040_1040 ;
      VIA 159.04 206.64 uart_rx_via3_4_8960_1800_2_8_1040_1040 ;
      VIA 159.04 206.64 uart_rx_via2_3_8960_1800_2_8_1040_1040 ;
      VIA 159.04 206.64 uart_rx_via1_2_8960_1800_2_8_1040_1040 ;
      VIA 159.04 196.56 uart_rx_via3_4_8960_1800_2_8_1040_1040 ;
      VIA 159.04 196.56 uart_rx_via2_3_8960_1800_2_8_1040_1040 ;
      VIA 159.04 196.56 uart_rx_via1_2_8960_1800_2_8_1040_1040 ;
      VIA 159.04 186.48 uart_rx_via3_4_8960_1800_2_8_1040_1040 ;
      VIA 159.04 186.48 uart_rx_via2_3_8960_1800_2_8_1040_1040 ;
      VIA 159.04 186.48 uart_rx_via1_2_8960_1800_2_8_1040_1040 ;
      VIA 159.04 176.4 uart_rx_via3_4_8960_1800_2_8_1040_1040 ;
      VIA 159.04 176.4 uart_rx_via2_3_8960_1800_2_8_1040_1040 ;
      VIA 159.04 176.4 uart_rx_via1_2_8960_1800_2_8_1040_1040 ;
      VIA 159.04 166.32 uart_rx_via3_4_8960_1800_2_8_1040_1040 ;
      VIA 159.04 166.32 uart_rx_via2_3_8960_1800_2_8_1040_1040 ;
      VIA 159.04 166.32 uart_rx_via1_2_8960_1800_2_8_1040_1040 ;
      VIA 159.04 156.24 uart_rx_via3_4_8960_1800_2_8_1040_1040 ;
      VIA 159.04 156.24 uart_rx_via2_3_8960_1800_2_8_1040_1040 ;
      VIA 159.04 156.24 uart_rx_via1_2_8960_1800_2_8_1040_1040 ;
      VIA 159.04 146.16 uart_rx_via3_4_8960_1800_2_8_1040_1040 ;
      VIA 159.04 146.16 uart_rx_via2_3_8960_1800_2_8_1040_1040 ;
      VIA 159.04 146.16 uart_rx_via1_2_8960_1800_2_8_1040_1040 ;
      VIA 159.04 136.08 uart_rx_via3_4_8960_1800_2_8_1040_1040 ;
      VIA 159.04 136.08 uart_rx_via2_3_8960_1800_2_8_1040_1040 ;
      VIA 159.04 136.08 uart_rx_via1_2_8960_1800_2_8_1040_1040 ;
      VIA 159.04 126 uart_rx_via3_4_8960_1800_2_8_1040_1040 ;
      VIA 159.04 126 uart_rx_via2_3_8960_1800_2_8_1040_1040 ;
      VIA 159.04 126 uart_rx_via1_2_8960_1800_2_8_1040_1040 ;
      VIA 159.04 115.92 uart_rx_via3_4_8960_1800_2_8_1040_1040 ;
      VIA 159.04 115.92 uart_rx_via2_3_8960_1800_2_8_1040_1040 ;
      VIA 159.04 115.92 uart_rx_via1_2_8960_1800_2_8_1040_1040 ;
      VIA 159.04 105.84 uart_rx_via3_4_8960_1800_2_8_1040_1040 ;
      VIA 159.04 105.84 uart_rx_via2_3_8960_1800_2_8_1040_1040 ;
      VIA 159.04 105.84 uart_rx_via1_2_8960_1800_2_8_1040_1040 ;
      VIA 159.04 95.76 uart_rx_via3_4_8960_1800_2_8_1040_1040 ;
      VIA 159.04 95.76 uart_rx_via2_3_8960_1800_2_8_1040_1040 ;
      VIA 159.04 95.76 uart_rx_via1_2_8960_1800_2_8_1040_1040 ;
      VIA 159.04 85.68 uart_rx_via3_4_8960_1800_2_8_1040_1040 ;
      VIA 159.04 85.68 uart_rx_via2_3_8960_1800_2_8_1040_1040 ;
      VIA 159.04 85.68 uart_rx_via1_2_8960_1800_2_8_1040_1040 ;
      VIA 159.04 75.6 uart_rx_via3_4_8960_1800_2_8_1040_1040 ;
      VIA 159.04 75.6 uart_rx_via2_3_8960_1800_2_8_1040_1040 ;
      VIA 159.04 75.6 uart_rx_via1_2_8960_1800_2_8_1040_1040 ;
      VIA 159.04 65.52 uart_rx_via3_4_8960_1800_2_8_1040_1040 ;
      VIA 159.04 65.52 uart_rx_via2_3_8960_1800_2_8_1040_1040 ;
      VIA 159.04 65.52 uart_rx_via1_2_8960_1800_2_8_1040_1040 ;
      VIA 159.04 55.44 uart_rx_via3_4_8960_1800_2_8_1040_1040 ;
      VIA 159.04 55.44 uart_rx_via2_3_8960_1800_2_8_1040_1040 ;
      VIA 159.04 55.44 uart_rx_via1_2_8960_1800_2_8_1040_1040 ;
      VIA 159.04 45.36 uart_rx_via3_4_8960_1800_2_8_1040_1040 ;
      VIA 159.04 45.36 uart_rx_via2_3_8960_1800_2_8_1040_1040 ;
      VIA 159.04 45.36 uart_rx_via1_2_8960_1800_2_8_1040_1040 ;
      VIA 159.04 35.28 uart_rx_via3_4_8960_1800_2_8_1040_1040 ;
      VIA 159.04 35.28 uart_rx_via2_3_8960_1800_2_8_1040_1040 ;
      VIA 159.04 35.28 uart_rx_via1_2_8960_1800_2_8_1040_1040 ;
      VIA 159.04 25.2 uart_rx_via3_4_8960_1800_2_8_1040_1040 ;
      VIA 159.04 25.2 uart_rx_via2_3_8960_1800_2_8_1040_1040 ;
      VIA 159.04 25.2 uart_rx_via1_2_8960_1800_2_8_1040_1040 ;
      VIA 159.04 15.12 uart_rx_via3_4_8960_1800_2_8_1040_1040 ;
      VIA 159.04 15.12 uart_rx_via2_3_8960_1800_2_8_1040_1040 ;
      VIA 159.04 15.12 uart_rx_via1_2_8960_1800_2_8_1040_1040 ;
      VIA 159.04 5.04 uart_rx_via3_4_8960_1800_2_8_1040_1040 ;
      VIA 159.04 5.04 uart_rx_via2_3_8960_1800_2_8_1040_1040 ;
      VIA 159.04 5.04 uart_rx_via1_2_8960_1800_2_8_1040_1040 ;
      VIA 114.24 206.64 uart_rx_via3_4_8960_1800_2_8_1040_1040 ;
      VIA 114.24 206.64 uart_rx_via2_3_8960_1800_2_8_1040_1040 ;
      VIA 114.24 206.64 uart_rx_via1_2_8960_1800_2_8_1040_1040 ;
      VIA 114.24 196.56 uart_rx_via3_4_8960_1800_2_8_1040_1040 ;
      VIA 114.24 196.56 uart_rx_via2_3_8960_1800_2_8_1040_1040 ;
      VIA 114.24 196.56 uart_rx_via1_2_8960_1800_2_8_1040_1040 ;
      VIA 114.24 186.48 uart_rx_via3_4_8960_1800_2_8_1040_1040 ;
      VIA 114.24 186.48 uart_rx_via2_3_8960_1800_2_8_1040_1040 ;
      VIA 114.24 186.48 uart_rx_via1_2_8960_1800_2_8_1040_1040 ;
      VIA 114.24 176.4 uart_rx_via3_4_8960_1800_2_8_1040_1040 ;
      VIA 114.24 176.4 uart_rx_via2_3_8960_1800_2_8_1040_1040 ;
      VIA 114.24 176.4 uart_rx_via1_2_8960_1800_2_8_1040_1040 ;
      VIA 114.24 166.32 uart_rx_via3_4_8960_1800_2_8_1040_1040 ;
      VIA 114.24 166.32 uart_rx_via2_3_8960_1800_2_8_1040_1040 ;
      VIA 114.24 166.32 uart_rx_via1_2_8960_1800_2_8_1040_1040 ;
      VIA 114.24 156.24 uart_rx_via3_4_8960_1800_2_8_1040_1040 ;
      VIA 114.24 156.24 uart_rx_via2_3_8960_1800_2_8_1040_1040 ;
      VIA 114.24 156.24 uart_rx_via1_2_8960_1800_2_8_1040_1040 ;
      VIA 114.24 146.16 uart_rx_via3_4_8960_1800_2_8_1040_1040 ;
      VIA 114.24 146.16 uart_rx_via2_3_8960_1800_2_8_1040_1040 ;
      VIA 114.24 146.16 uart_rx_via1_2_8960_1800_2_8_1040_1040 ;
      VIA 114.24 136.08 uart_rx_via3_4_8960_1800_2_8_1040_1040 ;
      VIA 114.24 136.08 uart_rx_via2_3_8960_1800_2_8_1040_1040 ;
      VIA 114.24 136.08 uart_rx_via1_2_8960_1800_2_8_1040_1040 ;
      VIA 114.24 126 uart_rx_via3_4_8960_1800_2_8_1040_1040 ;
      VIA 114.24 126 uart_rx_via2_3_8960_1800_2_8_1040_1040 ;
      VIA 114.24 126 uart_rx_via1_2_8960_1800_2_8_1040_1040 ;
      VIA 114.24 115.92 uart_rx_via3_4_8960_1800_2_8_1040_1040 ;
      VIA 114.24 115.92 uart_rx_via2_3_8960_1800_2_8_1040_1040 ;
      VIA 114.24 115.92 uart_rx_via1_2_8960_1800_2_8_1040_1040 ;
      VIA 114.24 105.84 uart_rx_via3_4_8960_1800_2_8_1040_1040 ;
      VIA 114.24 105.84 uart_rx_via2_3_8960_1800_2_8_1040_1040 ;
      VIA 114.24 105.84 uart_rx_via1_2_8960_1800_2_8_1040_1040 ;
      VIA 114.24 95.76 uart_rx_via3_4_8960_1800_2_8_1040_1040 ;
      VIA 114.24 95.76 uart_rx_via2_3_8960_1800_2_8_1040_1040 ;
      VIA 114.24 95.76 uart_rx_via1_2_8960_1800_2_8_1040_1040 ;
      VIA 114.24 85.68 uart_rx_via3_4_8960_1800_2_8_1040_1040 ;
      VIA 114.24 85.68 uart_rx_via2_3_8960_1800_2_8_1040_1040 ;
      VIA 114.24 85.68 uart_rx_via1_2_8960_1800_2_8_1040_1040 ;
      VIA 114.24 75.6 uart_rx_via3_4_8960_1800_2_8_1040_1040 ;
      VIA 114.24 75.6 uart_rx_via2_3_8960_1800_2_8_1040_1040 ;
      VIA 114.24 75.6 uart_rx_via1_2_8960_1800_2_8_1040_1040 ;
      VIA 114.24 65.52 uart_rx_via3_4_8960_1800_2_8_1040_1040 ;
      VIA 114.24 65.52 uart_rx_via2_3_8960_1800_2_8_1040_1040 ;
      VIA 114.24 65.52 uart_rx_via1_2_8960_1800_2_8_1040_1040 ;
      VIA 114.24 55.44 uart_rx_via3_4_8960_1800_2_8_1040_1040 ;
      VIA 114.24 55.44 uart_rx_via2_3_8960_1800_2_8_1040_1040 ;
      VIA 114.24 55.44 uart_rx_via1_2_8960_1800_2_8_1040_1040 ;
      VIA 114.24 45.36 uart_rx_via3_4_8960_1800_2_8_1040_1040 ;
      VIA 114.24 45.36 uart_rx_via2_3_8960_1800_2_8_1040_1040 ;
      VIA 114.24 45.36 uart_rx_via1_2_8960_1800_2_8_1040_1040 ;
      VIA 114.24 35.28 uart_rx_via3_4_8960_1800_2_8_1040_1040 ;
      VIA 114.24 35.28 uart_rx_via2_3_8960_1800_2_8_1040_1040 ;
      VIA 114.24 35.28 uart_rx_via1_2_8960_1800_2_8_1040_1040 ;
      VIA 114.24 25.2 uart_rx_via3_4_8960_1800_2_8_1040_1040 ;
      VIA 114.24 25.2 uart_rx_via2_3_8960_1800_2_8_1040_1040 ;
      VIA 114.24 25.2 uart_rx_via1_2_8960_1800_2_8_1040_1040 ;
      VIA 114.24 15.12 uart_rx_via3_4_8960_1800_2_8_1040_1040 ;
      VIA 114.24 15.12 uart_rx_via2_3_8960_1800_2_8_1040_1040 ;
      VIA 114.24 15.12 uart_rx_via1_2_8960_1800_2_8_1040_1040 ;
      VIA 114.24 5.04 uart_rx_via3_4_8960_1800_2_8_1040_1040 ;
      VIA 114.24 5.04 uart_rx_via2_3_8960_1800_2_8_1040_1040 ;
      VIA 114.24 5.04 uart_rx_via1_2_8960_1800_2_8_1040_1040 ;
      VIA 69.44 206.64 uart_rx_via3_4_8960_1800_2_8_1040_1040 ;
      VIA 69.44 206.64 uart_rx_via2_3_8960_1800_2_8_1040_1040 ;
      VIA 69.44 206.64 uart_rx_via1_2_8960_1800_2_8_1040_1040 ;
      VIA 69.44 196.56 uart_rx_via3_4_8960_1800_2_8_1040_1040 ;
      VIA 69.44 196.56 uart_rx_via2_3_8960_1800_2_8_1040_1040 ;
      VIA 69.44 196.56 uart_rx_via1_2_8960_1800_2_8_1040_1040 ;
      VIA 69.44 186.48 uart_rx_via3_4_8960_1800_2_8_1040_1040 ;
      VIA 69.44 186.48 uart_rx_via2_3_8960_1800_2_8_1040_1040 ;
      VIA 69.44 186.48 uart_rx_via1_2_8960_1800_2_8_1040_1040 ;
      VIA 69.44 176.4 uart_rx_via3_4_8960_1800_2_8_1040_1040 ;
      VIA 69.44 176.4 uart_rx_via2_3_8960_1800_2_8_1040_1040 ;
      VIA 69.44 176.4 uart_rx_via1_2_8960_1800_2_8_1040_1040 ;
      VIA 69.44 166.32 uart_rx_via3_4_8960_1800_2_8_1040_1040 ;
      VIA 69.44 166.32 uart_rx_via2_3_8960_1800_2_8_1040_1040 ;
      VIA 69.44 166.32 uart_rx_via1_2_8960_1800_2_8_1040_1040 ;
      VIA 69.44 156.24 uart_rx_via3_4_8960_1800_2_8_1040_1040 ;
      VIA 69.44 156.24 uart_rx_via2_3_8960_1800_2_8_1040_1040 ;
      VIA 69.44 156.24 uart_rx_via1_2_8960_1800_2_8_1040_1040 ;
      VIA 69.44 146.16 uart_rx_via3_4_8960_1800_2_8_1040_1040 ;
      VIA 69.44 146.16 uart_rx_via2_3_8960_1800_2_8_1040_1040 ;
      VIA 69.44 146.16 uart_rx_via1_2_8960_1800_2_8_1040_1040 ;
      VIA 69.44 136.08 uart_rx_via3_4_8960_1800_2_8_1040_1040 ;
      VIA 69.44 136.08 uart_rx_via2_3_8960_1800_2_8_1040_1040 ;
      VIA 69.44 136.08 uart_rx_via1_2_8960_1800_2_8_1040_1040 ;
      VIA 69.44 126 uart_rx_via3_4_8960_1800_2_8_1040_1040 ;
      VIA 69.44 126 uart_rx_via2_3_8960_1800_2_8_1040_1040 ;
      VIA 69.44 126 uart_rx_via1_2_8960_1800_2_8_1040_1040 ;
      VIA 69.44 115.92 uart_rx_via3_4_8960_1800_2_8_1040_1040 ;
      VIA 69.44 115.92 uart_rx_via2_3_8960_1800_2_8_1040_1040 ;
      VIA 69.44 115.92 uart_rx_via1_2_8960_1800_2_8_1040_1040 ;
      VIA 69.44 105.84 uart_rx_via3_4_8960_1800_2_8_1040_1040 ;
      VIA 69.44 105.84 uart_rx_via2_3_8960_1800_2_8_1040_1040 ;
      VIA 69.44 105.84 uart_rx_via1_2_8960_1800_2_8_1040_1040 ;
      VIA 69.44 95.76 uart_rx_via3_4_8960_1800_2_8_1040_1040 ;
      VIA 69.44 95.76 uart_rx_via2_3_8960_1800_2_8_1040_1040 ;
      VIA 69.44 95.76 uart_rx_via1_2_8960_1800_2_8_1040_1040 ;
      VIA 69.44 85.68 uart_rx_via3_4_8960_1800_2_8_1040_1040 ;
      VIA 69.44 85.68 uart_rx_via2_3_8960_1800_2_8_1040_1040 ;
      VIA 69.44 85.68 uart_rx_via1_2_8960_1800_2_8_1040_1040 ;
      VIA 69.44 75.6 uart_rx_via3_4_8960_1800_2_8_1040_1040 ;
      VIA 69.44 75.6 uart_rx_via2_3_8960_1800_2_8_1040_1040 ;
      VIA 69.44 75.6 uart_rx_via1_2_8960_1800_2_8_1040_1040 ;
      VIA 69.44 65.52 uart_rx_via3_4_8960_1800_2_8_1040_1040 ;
      VIA 69.44 65.52 uart_rx_via2_3_8960_1800_2_8_1040_1040 ;
      VIA 69.44 65.52 uart_rx_via1_2_8960_1800_2_8_1040_1040 ;
      VIA 69.44 55.44 uart_rx_via3_4_8960_1800_2_8_1040_1040 ;
      VIA 69.44 55.44 uart_rx_via2_3_8960_1800_2_8_1040_1040 ;
      VIA 69.44 55.44 uart_rx_via1_2_8960_1800_2_8_1040_1040 ;
      VIA 69.44 45.36 uart_rx_via3_4_8960_1800_2_8_1040_1040 ;
      VIA 69.44 45.36 uart_rx_via2_3_8960_1800_2_8_1040_1040 ;
      VIA 69.44 45.36 uart_rx_via1_2_8960_1800_2_8_1040_1040 ;
      VIA 69.44 35.28 uart_rx_via3_4_8960_1800_2_8_1040_1040 ;
      VIA 69.44 35.28 uart_rx_via2_3_8960_1800_2_8_1040_1040 ;
      VIA 69.44 35.28 uart_rx_via1_2_8960_1800_2_8_1040_1040 ;
      VIA 69.44 25.2 uart_rx_via3_4_8960_1800_2_8_1040_1040 ;
      VIA 69.44 25.2 uart_rx_via2_3_8960_1800_2_8_1040_1040 ;
      VIA 69.44 25.2 uart_rx_via1_2_8960_1800_2_8_1040_1040 ;
      VIA 69.44 15.12 uart_rx_via3_4_8960_1800_2_8_1040_1040 ;
      VIA 69.44 15.12 uart_rx_via2_3_8960_1800_2_8_1040_1040 ;
      VIA 69.44 15.12 uart_rx_via1_2_8960_1800_2_8_1040_1040 ;
      VIA 69.44 5.04 uart_rx_via3_4_8960_1800_2_8_1040_1040 ;
      VIA 69.44 5.04 uart_rx_via2_3_8960_1800_2_8_1040_1040 ;
      VIA 69.44 5.04 uart_rx_via1_2_8960_1800_2_8_1040_1040 ;
      VIA 24.64 206.64 uart_rx_via3_4_8960_1800_2_8_1040_1040 ;
      VIA 24.64 206.64 uart_rx_via2_3_8960_1800_2_8_1040_1040 ;
      VIA 24.64 206.64 uart_rx_via1_2_8960_1800_2_8_1040_1040 ;
      VIA 24.64 196.56 uart_rx_via3_4_8960_1800_2_8_1040_1040 ;
      VIA 24.64 196.56 uart_rx_via2_3_8960_1800_2_8_1040_1040 ;
      VIA 24.64 196.56 uart_rx_via1_2_8960_1800_2_8_1040_1040 ;
      VIA 24.64 186.48 uart_rx_via3_4_8960_1800_2_8_1040_1040 ;
      VIA 24.64 186.48 uart_rx_via2_3_8960_1800_2_8_1040_1040 ;
      VIA 24.64 186.48 uart_rx_via1_2_8960_1800_2_8_1040_1040 ;
      VIA 24.64 176.4 uart_rx_via3_4_8960_1800_2_8_1040_1040 ;
      VIA 24.64 176.4 uart_rx_via2_3_8960_1800_2_8_1040_1040 ;
      VIA 24.64 176.4 uart_rx_via1_2_8960_1800_2_8_1040_1040 ;
      VIA 24.64 166.32 uart_rx_via3_4_8960_1800_2_8_1040_1040 ;
      VIA 24.64 166.32 uart_rx_via2_3_8960_1800_2_8_1040_1040 ;
      VIA 24.64 166.32 uart_rx_via1_2_8960_1800_2_8_1040_1040 ;
      VIA 24.64 156.24 uart_rx_via3_4_8960_1800_2_8_1040_1040 ;
      VIA 24.64 156.24 uart_rx_via2_3_8960_1800_2_8_1040_1040 ;
      VIA 24.64 156.24 uart_rx_via1_2_8960_1800_2_8_1040_1040 ;
      VIA 24.64 146.16 uart_rx_via3_4_8960_1800_2_8_1040_1040 ;
      VIA 24.64 146.16 uart_rx_via2_3_8960_1800_2_8_1040_1040 ;
      VIA 24.64 146.16 uart_rx_via1_2_8960_1800_2_8_1040_1040 ;
      VIA 24.64 136.08 uart_rx_via3_4_8960_1800_2_8_1040_1040 ;
      VIA 24.64 136.08 uart_rx_via2_3_8960_1800_2_8_1040_1040 ;
      VIA 24.64 136.08 uart_rx_via1_2_8960_1800_2_8_1040_1040 ;
      VIA 24.64 126 uart_rx_via3_4_8960_1800_2_8_1040_1040 ;
      VIA 24.64 126 uart_rx_via2_3_8960_1800_2_8_1040_1040 ;
      VIA 24.64 126 uart_rx_via1_2_8960_1800_2_8_1040_1040 ;
      VIA 24.64 115.92 uart_rx_via3_4_8960_1800_2_8_1040_1040 ;
      VIA 24.64 115.92 uart_rx_via2_3_8960_1800_2_8_1040_1040 ;
      VIA 24.64 115.92 uart_rx_via1_2_8960_1800_2_8_1040_1040 ;
      VIA 24.64 105.84 uart_rx_via3_4_8960_1800_2_8_1040_1040 ;
      VIA 24.64 105.84 uart_rx_via2_3_8960_1800_2_8_1040_1040 ;
      VIA 24.64 105.84 uart_rx_via1_2_8960_1800_2_8_1040_1040 ;
      VIA 24.64 95.76 uart_rx_via3_4_8960_1800_2_8_1040_1040 ;
      VIA 24.64 95.76 uart_rx_via2_3_8960_1800_2_8_1040_1040 ;
      VIA 24.64 95.76 uart_rx_via1_2_8960_1800_2_8_1040_1040 ;
      VIA 24.64 85.68 uart_rx_via3_4_8960_1800_2_8_1040_1040 ;
      VIA 24.64 85.68 uart_rx_via2_3_8960_1800_2_8_1040_1040 ;
      VIA 24.64 85.68 uart_rx_via1_2_8960_1800_2_8_1040_1040 ;
      VIA 24.64 75.6 uart_rx_via3_4_8960_1800_2_8_1040_1040 ;
      VIA 24.64 75.6 uart_rx_via2_3_8960_1800_2_8_1040_1040 ;
      VIA 24.64 75.6 uart_rx_via1_2_8960_1800_2_8_1040_1040 ;
      VIA 24.64 65.52 uart_rx_via3_4_8960_1800_2_8_1040_1040 ;
      VIA 24.64 65.52 uart_rx_via2_3_8960_1800_2_8_1040_1040 ;
      VIA 24.64 65.52 uart_rx_via1_2_8960_1800_2_8_1040_1040 ;
      VIA 24.64 55.44 uart_rx_via3_4_8960_1800_2_8_1040_1040 ;
      VIA 24.64 55.44 uart_rx_via2_3_8960_1800_2_8_1040_1040 ;
      VIA 24.64 55.44 uart_rx_via1_2_8960_1800_2_8_1040_1040 ;
      VIA 24.64 45.36 uart_rx_via3_4_8960_1800_2_8_1040_1040 ;
      VIA 24.64 45.36 uart_rx_via2_3_8960_1800_2_8_1040_1040 ;
      VIA 24.64 45.36 uart_rx_via1_2_8960_1800_2_8_1040_1040 ;
      VIA 24.64 35.28 uart_rx_via3_4_8960_1800_2_8_1040_1040 ;
      VIA 24.64 35.28 uart_rx_via2_3_8960_1800_2_8_1040_1040 ;
      VIA 24.64 35.28 uart_rx_via1_2_8960_1800_2_8_1040_1040 ;
      VIA 24.64 25.2 uart_rx_via3_4_8960_1800_2_8_1040_1040 ;
      VIA 24.64 25.2 uart_rx_via2_3_8960_1800_2_8_1040_1040 ;
      VIA 24.64 25.2 uart_rx_via1_2_8960_1800_2_8_1040_1040 ;
      VIA 24.64 15.12 uart_rx_via3_4_8960_1800_2_8_1040_1040 ;
      VIA 24.64 15.12 uart_rx_via2_3_8960_1800_2_8_1040_1040 ;
      VIA 24.64 15.12 uart_rx_via1_2_8960_1800_2_8_1040_1040 ;
      VIA 24.64 5.04 uart_rx_via3_4_8960_1800_2_8_1040_1040 ;
      VIA 24.64 5.04 uart_rx_via2_3_8960_1800_2_8_1040_1040 ;
      VIA 24.64 5.04 uart_rx_via1_2_8960_1800_2_8_1040_1040 ;
    END
  END VSS
  PIN busy
    DIRECTION OUTPUT ;
    USE SIGNAL ;
    PORT
      LAYER Metal3 ;
        RECT  0 169.54 0.52 169.82 ;
    END
  END busy
  PIN clk
    DIRECTION INPUT ;
    USE SIGNAL ;
    PORT
      LAYER Metal3 ;
        RECT  0 197.54 0.52 197.82 ;
    END
  END clk
  PIN frame_error
    DIRECTION OUTPUT ;
    USE SIGNAL ;
    PORT
      LAYER Metal3 ;
        RECT  0 151.62 0.52 151.9 ;
    END
  END frame_error
  PIN m_axis_tdata[0]
    DIRECTION OUTPUT ;
    USE SIGNAL ;
    PORT
      LAYER Metal3 ;
        RECT  0 185.22 0.52 185.5 ;
    END
  END m_axis_tdata[0]
  PIN m_axis_tdata[1]
    DIRECTION OUTPUT ;
    USE SIGNAL ;
    PORT
      LAYER Metal3 ;
        RECT  0 160.58 0.52 160.86 ;
    END
  END m_axis_tdata[1]
  PIN m_axis_tdata[2]
    DIRECTION OUTPUT ;
    USE SIGNAL ;
    PORT
      LAYER Metal3 ;
        RECT  0 203.14 0.52 203.42 ;
    END
  END m_axis_tdata[2]
  PIN m_axis_tdata[3]
    DIRECTION OUTPUT ;
    USE SIGNAL ;
    PORT
      LAYER Metal3 ;
        RECT  0 198.66 0.52 198.94 ;
    END
  END m_axis_tdata[3]
  PIN m_axis_tdata[4]
    DIRECTION OUTPUT ;
    USE SIGNAL ;
    PORT
      LAYER Metal3 ;
        RECT  0 202.02 0.52 202.3 ;
    END
  END m_axis_tdata[4]
  PIN m_axis_tdata[5]
    DIRECTION OUTPUT ;
    USE SIGNAL ;
    PORT
      LAYER Metal3 ;
        RECT  0 200.9 0.52 201.18 ;
    END
  END m_axis_tdata[5]
  PIN m_axis_tdata[6]
    DIRECTION OUTPUT ;
    USE SIGNAL ;
    PORT
      LAYER Metal3 ;
        RECT  0 199.78 0.52 200.06 ;
    END
  END m_axis_tdata[6]
  PIN m_axis_tdata[7]
    DIRECTION OUTPUT ;
    USE SIGNAL ;
    PORT
      LAYER Metal3 ;
        RECT  0 179.62 0.52 179.9 ;
    END
  END m_axis_tdata[7]
  PIN m_axis_tready
    DIRECTION INPUT ;
    USE SIGNAL ;
    PORT
      LAYER Metal3 ;
        RECT  0 140.42 0.52 140.7 ;
    END
  END m_axis_tready
  PIN m_axis_tvalid
    DIRECTION OUTPUT ;
    USE SIGNAL ;
    PORT
      LAYER Metal3 ;
        RECT  0 141.54 0.52 141.82 ;
    END
  END m_axis_tvalid
  PIN overrun_error
    DIRECTION OUTPUT ;
    USE SIGNAL ;
    PORT
      LAYER Metal3 ;
        RECT  0 139.3 0.52 139.58 ;
    END
  END overrun_error
  PIN prescale[0]
    DIRECTION INPUT ;
    USE SIGNAL ;
    PORT
      LAYER Metal3 ;
        RECT  0 102.34 0.52 102.62 ;
    END
  END prescale[0]
  PIN prescale[10]
    DIRECTION INPUT ;
    USE SIGNAL ;
    PORT
      LAYER Metal3 ;
        RECT  0 16.1 0.52 16.38 ;
    END
  END prescale[10]
  PIN prescale[11]
    DIRECTION INPUT ;
    USE SIGNAL ;
    PORT
      LAYER Metal3 ;
        RECT  0 18.34 0.52 18.62 ;
    END
  END prescale[11]
  PIN prescale[12]
    DIRECTION INPUT ;
    USE SIGNAL ;
    PORT
      LAYER Metal3 ;
        RECT  0 19.46 0.52 19.74 ;
    END
  END prescale[12]
  PIN prescale[13]
    DIRECTION INPUT ;
    USE SIGNAL ;
    PORT
      LAYER Metal3 ;
        RECT  0 20.58 0.52 20.86 ;
    END
  END prescale[13]
  PIN prescale[14]
    DIRECTION INPUT ;
    USE SIGNAL ;
    PORT
      LAYER Metal3 ;
        RECT  0 56.42 0.52 56.7 ;
    END
  END prescale[14]
  PIN prescale[15]
    DIRECTION INPUT ;
    USE SIGNAL ;
    PORT
      LAYER Metal3 ;
        RECT  0 57.54 0.52 57.82 ;
    END
  END prescale[15]
  PIN prescale[1]
    DIRECTION INPUT ;
    USE SIGNAL ;
    PORT
      LAYER Metal3 ;
        RECT  0 101.22 0.52 101.5 ;
    END
  END prescale[1]
  PIN prescale[2]
    DIRECTION INPUT ;
    USE SIGNAL ;
    PORT
      LAYER Metal3 ;
        RECT  0 100.1 0.52 100.38 ;
    END
  END prescale[2]
  PIN prescale[3]
    DIRECTION INPUT ;
    USE SIGNAL ;
    PORT
      LAYER Metal3 ;
        RECT  0 98.98 0.52 99.26 ;
    END
  END prescale[3]
  PIN prescale[4]
    DIRECTION INPUT ;
    USE SIGNAL ;
    PORT
      LAYER Metal3 ;
        RECT  0 81.06 0.52 81.34 ;
    END
  END prescale[4]
  PIN prescale[5]
    DIRECTION INPUT ;
    USE SIGNAL ;
    PORT
      LAYER Metal3 ;
        RECT  0 76.58 0.52 76.86 ;
    END
  END prescale[5]
  PIN prescale[6]
    DIRECTION INPUT ;
    USE SIGNAL ;
    PORT
      LAYER Metal3 ;
        RECT  0 51.94 0.52 52.22 ;
    END
  END prescale[6]
  PIN prescale[7]
    DIRECTION INPUT ;
    USE SIGNAL ;
    PORT
      LAYER Metal3 ;
        RECT  0 29.54 0.52 29.82 ;
    END
  END prescale[7]
  PIN prescale[8]
    DIRECTION INPUT ;
    USE SIGNAL ;
    PORT
      LAYER Metal3 ;
        RECT  0 31.78 0.52 32.06 ;
    END
  END prescale[8]
  PIN prescale[9]
    DIRECTION INPUT ;
    USE SIGNAL ;
    PORT
      LAYER Metal3 ;
        RECT  0 17.22 0.52 17.5 ;
    END
  END prescale[9]
  PIN rst
    DIRECTION INPUT ;
    USE SIGNAL ;
    PORT
      LAYER Metal3 ;
        RECT  0 161.7 0.52 161.98 ;
    END
  END rst
  PIN rxd
    DIRECTION INPUT ;
    USE SIGNAL ;
    PORT
      LAYER Metal3 ;
        RECT  0 162.82 0.52 163.1 ;
    END
  END rxd
  OBS
    LAYER Metal1 ;
     RECT  0 4.59 214.48 212.13 ;
    LAYER Metal2 ;
     RECT  0 4.59 214.48 212.13 ;
    LAYER Metal3 ;
     RECT  0 4.59 214.48 212.13 ;
    LAYER Metal4 ;
     RECT  0 4.59 214.48 212.13 ;
  END
END uart_rx
END LIBRARY
